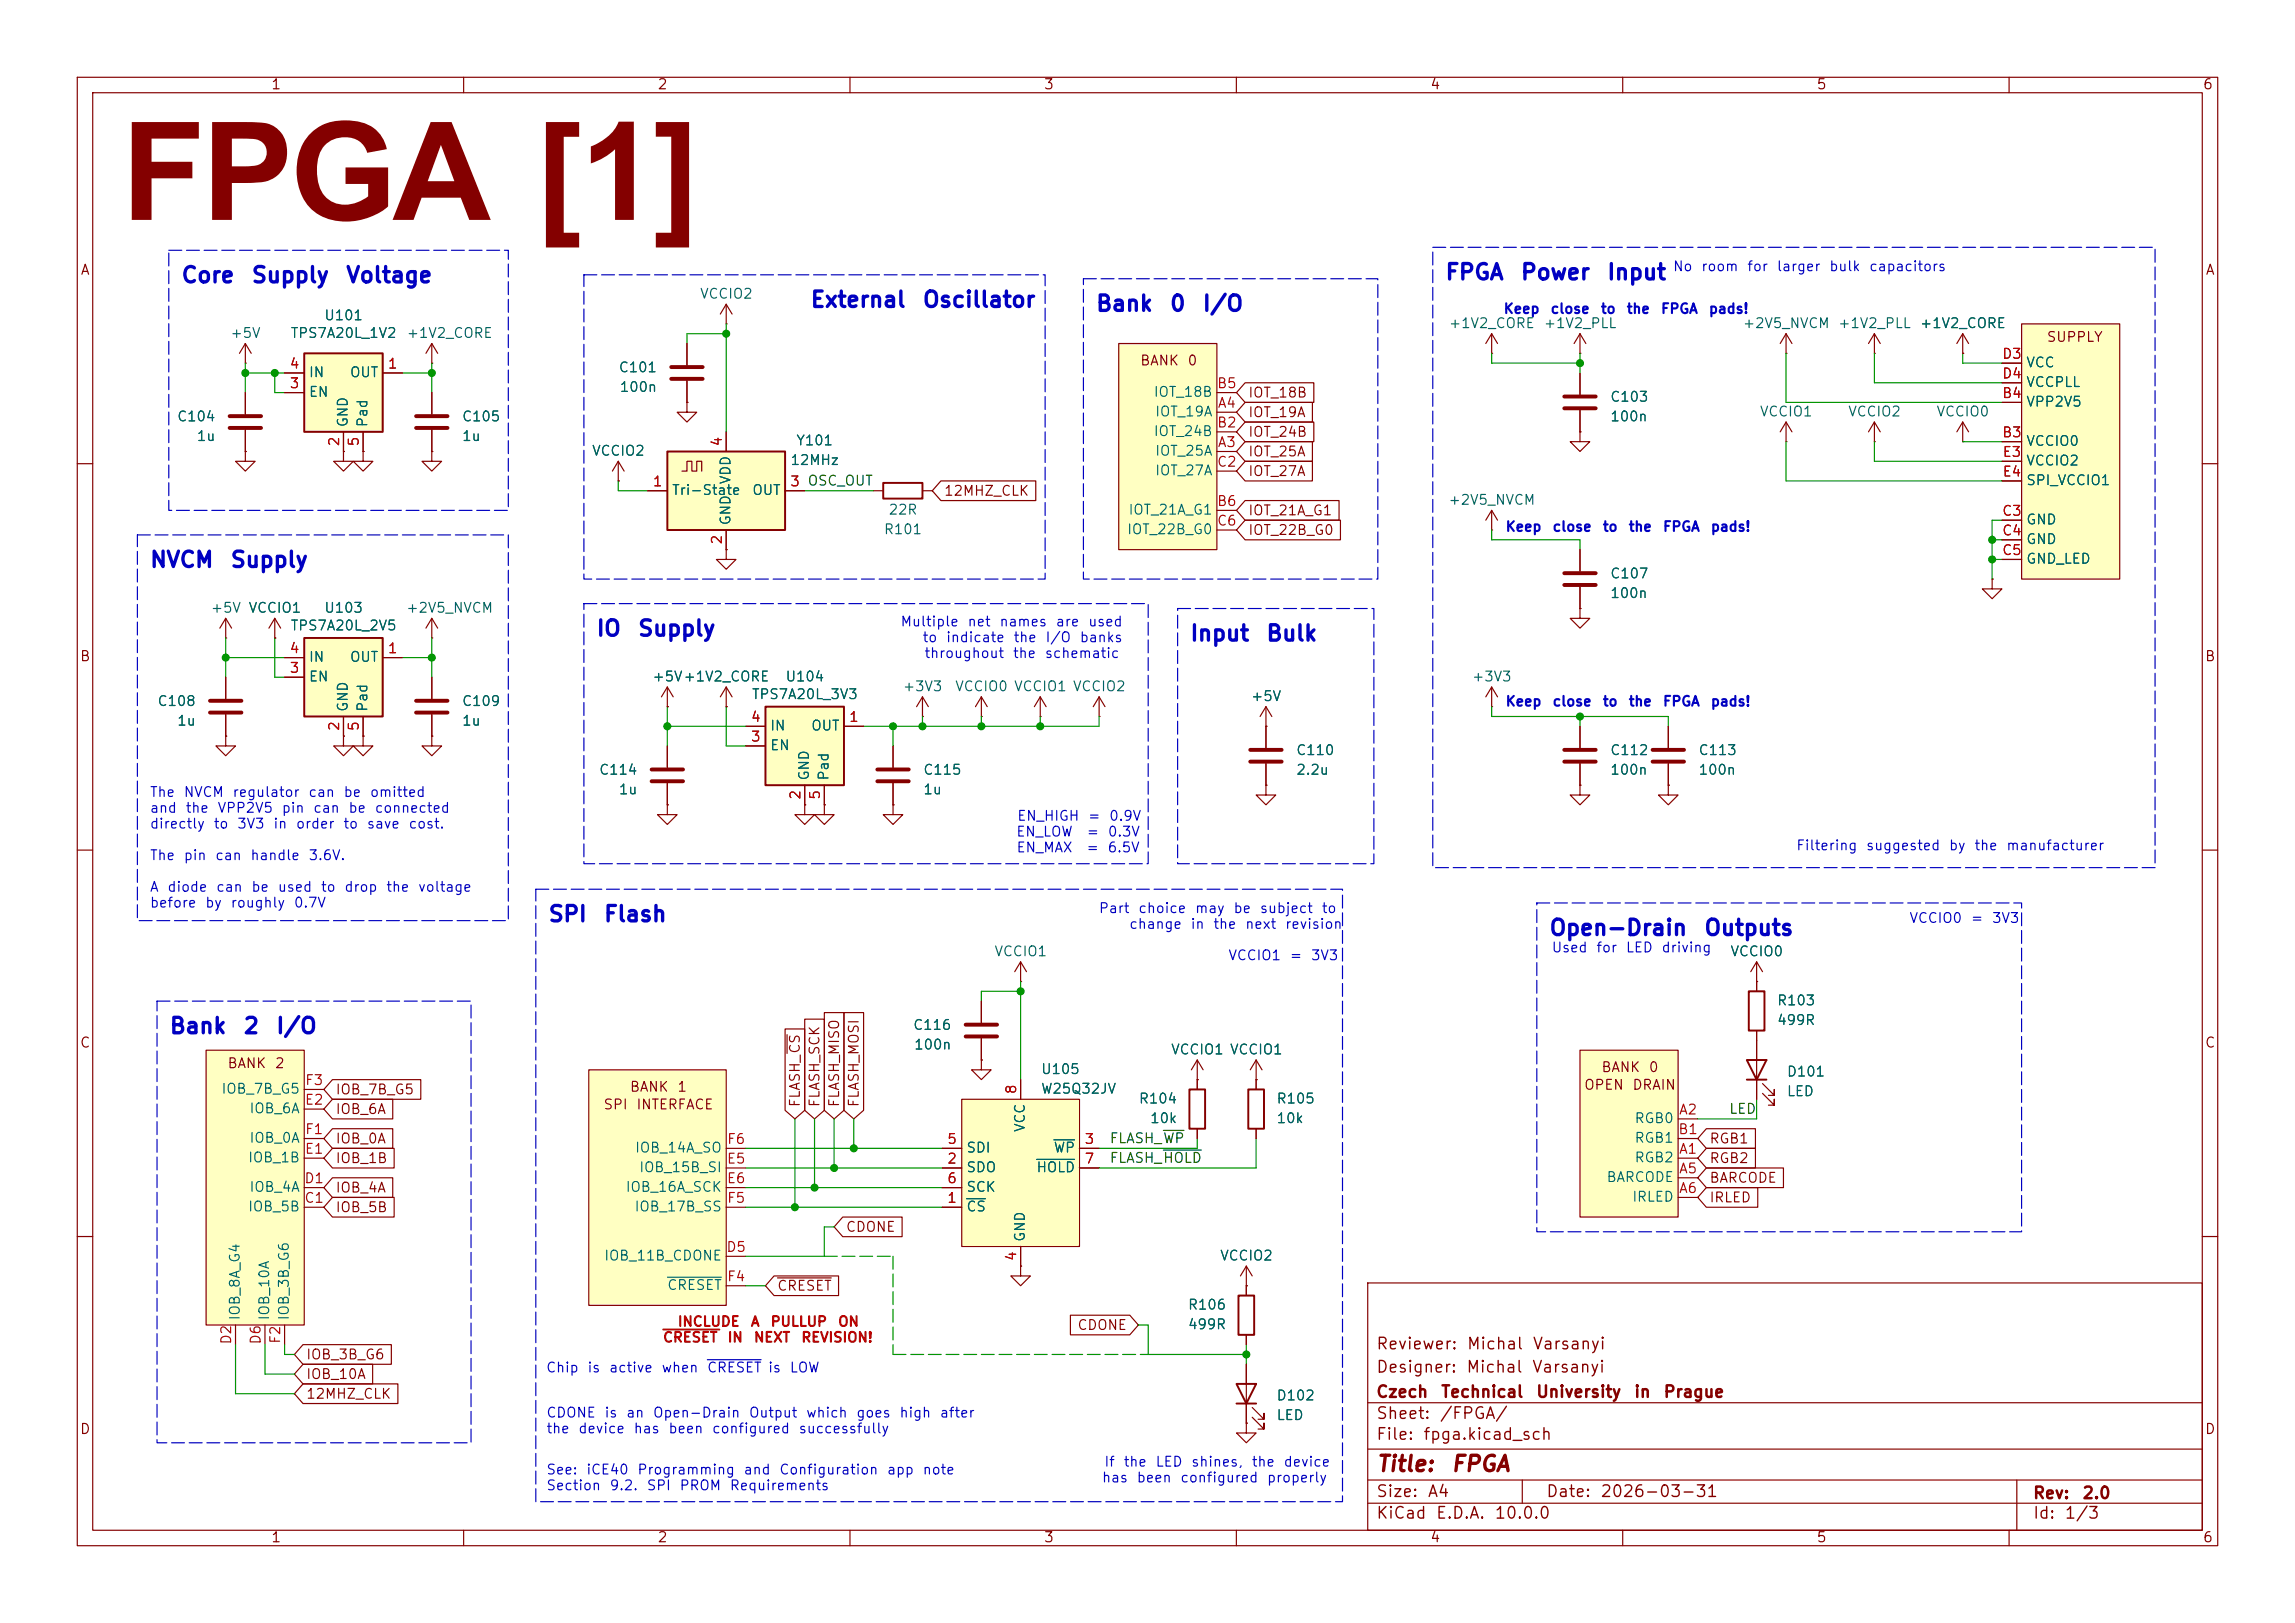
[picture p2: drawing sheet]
<svg xmlns="http://www.w3.org/2000/svg" width="297mm" height="210mm" viewBox="0 0 297 210" stroke-linecap="round" stroke-linejoin="round" font-family="sans-serif">
<defs><g id="words">
<text font-size="17.7" fill="#840000" x="15.7" y="28.5">FPGA [1]</text>
<g font-size="2" fill="#0000c2">
<text x="23.3" y="37.1">Core</text>
<text x="32.4" y="37.1">Supply</text>
<text x="44.7" y="37.1">Voltage</text>
<text x="104.8" y="40.3">External</text>
<text x="119.3" y="40.3">Oscillator</text>
<text x="141.7" y="40.8">Bank</text>
<text x="151.3" y="40.8">0</text>
<text x="155.5" y="40.8">I/O</text>
<text x="186.9" y="36.7">FPGA</text>
<text x="196.7" y="36.7">Power</text>
<text x="207.9" y="36.7">Input</text>
<text x="19.3" y="73.9">NVCM</text>
<text x="29.7" y="73.9">Supply</text>
<text x="77.1" y="82.8">IO</text>
<text x="82.4" y="82.8">Supply</text>
<text x="153.9" y="83.4">Input</text>
<text x="163.7" y="83.4">Bulk</text>
<text x="70.8" y="119.8">SPI</text>
<text x="78" y="119.8">Flash</text>
<text x="200.4" y="121.5">Open-Drain</text>
<text x="220.4" y="121.5">Outputs</text>
<text x="21.8" y="134.2">Bank</text>
<text x="31.4" y="134.2">2</text>
<text x="35.6" y="134.2">I/O</text>
</g>
<g font-size="2" fill="#840000">
<text x="178" y="190.9">Title:</text>
<text x="187.7" y="190.9">FPGA</text>
</g>
<g font-size="1.5" fill="#840000">
<text x="178" y="178">Designer:</text>
<text x="178" y="175">Reviewer:</text>
<text x="189.7" y="178">Michal</text>
<text x="189.7" y="175">Michal</text>
<text x="198.2" y="178">Varsanyi</text>
<text x="198.2" y="175">Varsanyi</text>
<text x="178" y="184">Sheet:</text>
<text x="178" y="181.2">Czech</text>
<text x="186.2" y="184">/FPGA/</text>
<text x="186.4" y="181.2">Technical</text>
<text x="198.7" y="181.2">University</text>
<text x="211.4" y="181.2">in</text>
<text x="215.2" y="181.2">Prague</text>
<text x="178" y="186.7">File:</text>
<text x="184.1" y="186.7">fpga.kicad_sch</text>
<text x="178" y="196.9">KiCad</text>
<text x="178" y="194.1">Size:</text>
<text x="184.7" y="194.1">A4</text>
<text x="185.7" y="196.9">E.D.A.</text>
<text x="193.3" y="196.9">10.0.0</text>
<text x="200" y="194.1">Date:</text>
<text x="207" y="194.1">2026-03-31</text>
<text x="263" y="194.3">Rev:</text>
<text x="263" y="196.9">Id:</text>
<text x="267.1" y="196.9">1/3</text>
<text x="269.4" y="194.3">2.0</text>
</g>
<g font-size="1.3" fill="#840000">
<text x="35" y="11.9">1</text>
<text x="85" y="11.9">2</text>
<text x="135" y="11.9">3</text>
<text x="185" y="11.9">4</text>
<text x="235" y="11.9">5</text>
<text x="285" y="11.9">6</text>
<text x="10.3" y="35.9">A</text>
<text x="285.3" y="35.9">A</text>
<text x="147.5" y="47.6">BANK</text>
<text x="153.6" y="47.6">0</text>
<text x="264.8" y="44.6">SUPPLY</text>
<text x="161.4" y="51.8">IOT_18B</text>
<text x="161.4" y="54.3">IOT_19A</text>
<text x="161.4" y="56.8">IOT_24B</text>
<text x="161.4" y="59.4">IOT_25A</text>
<text x="122.1" y="64.5">12MHZ_CLK</text>
<text x="161.4" y="61.9">IOT_27A</text>
<text x="161.4" y="67">IOT_21A_G1</text>
<text x="161.4" y="69.5">IOT_22B_G0</text>
<text x="10.3" y="85.9">B</text>
<text x="285.3" y="85.9">B</text>
<text x="10.3" y="135.9">C</text>
<text x="285.3" y="135.9">C</text>
<text x="29.4" y="138.5">BANK</text>
<text x="35.5" y="138.5">2</text>
<text x="43.3" y="141.9">IOB_7B_G5</text>
<text x="78" y="143.9">SPI</text>
<text x="81.4" y="141.6">BANK</text>
<text x="82.3" y="143.9">INTERFACE</text>
<text x="87.6" y="141.6">1</text>
<text x="103.8" y="143.4" transform="rotate(-90 103.8 143.4)">FLASH_CS</text>
<text x="106.4" y="143.4" transform="rotate(-90 106.4 143.4)">FLASH_SCK</text>
<text x="108.9" y="143.4" transform="rotate(-90 108.9 143.4)">FLASH_MISO</text>
<text x="111.4" y="143.4" transform="rotate(-90 111.4 143.4)">FLASH_MOSI</text>
<text x="204.9" y="141.3">OPEN</text>
<text x="207.2" y="139">BANK</text>
<text x="211.2" y="141.3">DRAIN</text>
<text x="213.3" y="139">0</text>
<text x="43.3" y="144.5">IOB_6A</text>
<text x="43.3" y="148.3">IOB_0A</text>
<text x="221.1" y="148.3">RGB1</text>
<text x="43.3" y="154.6">IOB_4A</text>
<text x="43.3" y="150.8">IOB_1B</text>
<text x="221.1" y="150.8">RGB2</text>
<text x="221.1" y="153.4">BARCODE</text>
<text x="221.1" y="155.9">IRLED</text>
<text x="43.3" y="157.2">IOB_5B</text>
<text x="109.4" y="159.7">CDONE</text>
<text x="100.5" y="167.3">CRESET</text>
<text x="139.3" y="172.4">CDONE</text>
<text x="39.5" y="178.8">IOB_10A</text>
<text x="39.5" y="176.2">IOB_3B_G6</text>
<text x="10.3" y="185.9">D</text>
<text x="39.5" y="181.3">12MHZ_CLK</text>
<text x="285.3" y="185.9">D</text>
<text x="35" y="199.9">1</text>
<text x="85" y="199.9">2</text>
<text x="135" y="199.9">3</text>
<text x="185" y="199.9">4</text>
<text x="235" y="199.9">5</text>
<text x="285" y="199.9">6</text>
</g>
<g font-size="1.3" fill="#0000c2">
<text x="216.4" y="35.4">No</text>
<text x="220.1" y="35.4">room</text>
<text x="226" y="35.4">for</text>
<text x="229.8" y="35.4">larger</text>
<text x="236.6" y="35.4">bulk</text>
<text x="241.8" y="35.4">capacitors</text>
<text x="194.5" y="40.9">Keep</text>
<text x="200.6" y="40.9">close</text>
<text x="207.1" y="40.9">to</text>
<text x="210.4" y="40.9">the</text>
<text x="214.9" y="40.9">FPGA</text>
<text x="221" y="40.9">pads!</text>
<text x="194.8" y="69.1">Keep</text>
<text x="200.8" y="69.1">close</text>
<text x="207.3" y="69.1">to</text>
<text x="210.7" y="69.1">the</text>
<text x="215.1" y="69.1">FPGA</text>
<text x="221.3" y="69.1">pads!</text>
<text x="116.4" y="81.4">Multiple</text>
<text x="119.3" y="83.4">to</text>
<text x="122.3" y="83.4">indicate</text>
<text x="125.1" y="81.4">net</text>
<text x="129.2" y="81.4">names</text>
<text x="131.1" y="83.4">the</text>
<text x="135.2" y="83.4">I/O</text>
<text x="136.5" y="81.4">are</text>
<text x="139.6" y="83.4">banks</text>
<text x="140.7" y="81.4">used</text>
<text x="119.5" y="85.5">throughout</text>
<text x="131" y="85.5">the</text>
<text x="135.1" y="85.5">schematic</text>
<text x="194.8" y="91.7">Keep</text>
<text x="200.8" y="91.7">close</text>
<text x="207.3" y="91.7">to</text>
<text x="210.7" y="91.7">the</text>
<text x="215.1" y="91.7">FPGA</text>
<text x="221.3" y="91.7">pads!</text>
<text x="19.3" y="103.4">The</text>
<text x="19.3" y="105.5">and</text>
<text x="19.3" y="107.5">directly</text>
<text x="23.7" y="103.4">NVCM</text>
<text x="23.9" y="105.5">the</text>
<text x="27.6" y="107.5">to</text>
<text x="28.1" y="105.5">VPP2V5</text>
<text x="30" y="103.4">regulator</text>
<text x="30.6" y="107.5">3V3</text>
<text x="35.3" y="107.5">in</text>
<text x="36.4" y="105.5">pin</text>
<text x="38.2" y="107.5">order</text>
<text x="39.8" y="103.4">can</text>
<text x="40.4" y="105.5">can</text>
<text x="44.3" y="107.5">to</text>
<text x="44.4" y="103.4">be</text>
<text x="45" y="105.5">be</text>
<text x="47.4" y="107.5">save</text>
<text x="47.8" y="103.4">omitted</text>
<text x="48.4" y="105.5">connected</text>
<text x="52.8" y="107.5">cost.</text>
<text x="131.5" y="106.5">EN_HIGH</text>
<text x="140.7" y="106.5">=</text>
<text x="143.4" y="106.5">0.9V</text>
<text x="19.3" y="111.6">The</text>
<text x="23.7" y="111.6">pin</text>
<text x="27.8" y="111.6">can</text>
<text x="32.3" y="111.6">handle</text>
<text x="39.8" y="111.6">3.6V.</text>
<text x="131.4" y="108.6">EN_LOW</text>
<text x="131.5" y="110.6">EN_MAX</text>
<text x="140.5" y="110.6">=</text>
<text x="140.5" y="108.6">=</text>
<text x="143.2" y="110.6">6.5V</text>
<text x="143.3" y="108.6">0.3V</text>
<text x="232.4" y="110.3">Filtering</text>
<text x="241.4" y="110.3">suggested</text>
<text x="252.1" y="110.3">by</text>
<text x="255.4" y="110.3">the</text>
<text x="259.5" y="110.3">manufacturer</text>
<text x="19.3" y="115.7">A</text>
<text x="19.3" y="117.8">before</text>
<text x="21.6" y="115.7">diode</text>
<text x="26.5" y="117.8">by</text>
<text x="27.9" y="115.7">can</text>
<text x="29.7" y="117.8">roughly</text>
<text x="32.4" y="115.7">be</text>
<text x="35.8" y="115.7">used</text>
<text x="37.9" y="117.8">0.7V</text>
<text x="41.4" y="115.7">to</text>
<text x="44.5" y="115.7">drop</text>
<text x="49.9" y="115.7">the</text>
<text x="54" y="115.7">voltage</text>
<text x="142.1" y="118.5">Part</text>
<text x="147.2" y="118.5">choice</text>
<text x="154.6" y="118.5">may</text>
<text x="159.5" y="118.5">be</text>
<text x="162.9" y="118.5">subject</text>
<text x="170.9" y="118.5">to</text>
<text x="247" y="119.7">VCCIO0</text>
<text x="254.9" y="119.7">=</text>
<text x="257.7" y="119.7">3V3</text>
<text x="146" y="120.5">change</text>
<text x="154" y="120.5">in</text>
<text x="156.9" y="120.5">the</text>
<text x="158.9" y="124.6">VCCIO1</text>
<text x="161" y="120.5">next</text>
<text x="166.2" y="120.5">revision</text>
<text x="166.8" y="124.6">=</text>
<text x="169.6" y="124.6">3V3</text>
<text x="200.7" y="123.5">Used</text>
<text x="206.5" y="123.5">for</text>
<text x="210.3" y="123.5">LED</text>
<text x="214.9" y="123.5">driving</text>
<text x="70.6" y="177.9">Chip</text>
<text x="75.9" y="177.9">is</text>
<text x="78.7" y="177.9">active</text>
<text x="85.5" y="177.9">when</text>
<text x="91.4" y="177.9">CRESET is</text>
<text x="102.1" y="177.9">LOW</text>
<text x="70.6" y="183.7">CDONE</text>
<text x="70.6" y="185.8">the</text>
<text x="74.7" y="185.8">device</text>
<text x="78.1" y="183.7">is</text>
<text x="80.9" y="183.7">an</text>
<text x="81.9" y="185.8">has</text>
<text x="84.4" y="183.7">Open-Drain</text>
<text x="86.4" y="185.8">been</text>
<text x="92" y="185.8">configured</text>
<text x="96.8" y="183.7">Output</text>
<text x="103.3" y="185.8">successfully</text>
<text x="104.2" y="183.7">which</text>
<text x="110.7" y="183.7">goes</text>
<text x="116.3" y="183.7">high</text>
<text x="121.5" y="183.7">after</text>
<text x="70.6" y="191.1">See:</text>
<text x="75.8" y="191.1">iCE40</text>
<text x="82.4" y="191.1">Programming</text>
<text x="96.1" y="191.1">and</text>
<text x="100.8" y="191.1">Configuration</text>
<text x="114.7" y="191.1">app</text>
<text x="119.3" y="191.1">note</text>
<text x="142.8" y="190.1">If</text>
<text x="145.3" y="190.1">the</text>
<text x="149.4" y="190.1">LED</text>
<text x="154.1" y="190.1">shines,</text>
<text x="161.9" y="190.1">the</text>
<text x="166" y="190.1">device</text>
<text x="70.6" y="193.2">Section</text>
<text x="78.8" y="193.2">9.2.</text>
<text x="83.6" y="193.2">SPI</text>
<text x="87.9" y="193.2">PROM</text>
<text x="94.3" y="193.2">Requirements</text>
<text x="142.5" y="192.1">has</text>
<text x="147" y="192.1">been</text>
<text x="152.7" y="192.1">configured</text>
<text x="163.9" y="192.1">properly</text>
</g>
<g font-size="1.3" fill="#006464">
<text x="41.9" y="41.8">U101</text>
<text x="90.5" y="39">VCCIO2</text>
<text x="29.7" y="44">+5V</text>
<text x="37.5" y="44">TPS7A20L_1V2</text>
<text x="52.5" y="44">+1V2_CORE</text>
<text x="187.4" y="42.8">+1V2_CORE</text>
<text x="199.7" y="42.8">+1V2_PLL</text>
<text x="225.4" y="42.8">+2V5_NVCM</text>
<text x="237.8" y="42.8">+1V2_PLL</text>
<text x="248.4" y="42.8">+1V2_CORE</text>
<text x="262.1" y="47.9">VCC</text>
<text x="39.9" y="51.7">EN</text>
<text x="39.9" y="49.1">IN</text>
<text x="45.2" y="49.1">OUT</text>
<text x="80" y="48.5">C101</text>
<text x="80.1" y="51">100n</text>
<text x="149.2" y="51.7">IOT_18B</text>
<text x="208.3" y="52.3">C103</text>
<text x="262.1" y="52.9">VPP2V5</text>
<text x="262.1" y="50.4">VCCPLL</text>
<text x="22.8" y="54.8">C104</text>
<text x="25.4" y="57.4">1u</text>
<text x="45.3" y="55.4" transform="rotate(-90 45.3 55.4)">GND</text>
<text x="47.9" y="55.4" transform="rotate(-90 47.9 55.4)">Pad</text>
<text x="59.7" y="54.8">C105</text>
<text x="59.7" y="57.4">1u</text>
<text x="76.5" y="59.3">VCCIO2</text>
<text x="102.9" y="57.9">Y101</text>
<text x="149.2" y="56.7">IOT_24B</text>
<text x="149.4" y="59.3">IOT_25A</text>
<text x="149.4" y="54.2">IOT_19A</text>
<text x="208.3" y="54.8">100n</text>
<text x="227.7" y="54.2">VCCIO1</text>
<text x="239.1" y="54.2">VCCIO2</text>
<text x="250.5" y="54.2">VCCIO0</text>
<text x="262.1" y="58">VCCIO0</text>
<text x="86.9" y="64.4">Tri-State</text>
<text x="94.8" y="62.8" transform="rotate(-90 94.8 62.8)">VDD</text>
<text x="97.3" y="64.4">OUT</text>
<text x="102.2" y="60.5">12MHz</text>
<text x="149.4" y="61.8">IOT_27A</text>
<text x="187.3" y="65.6">+2V5_NVCM</text>
<text x="262.1" y="60.6">VCCIO2</text>
<text x="262.1" y="63.1">SPI_VCCIO1</text>
<text x="94.8" y="68.1" transform="rotate(-90 94.8 68.1)">GND</text>
<text x="114.3" y="69.4">R101</text>
<text x="114.9" y="66.9">22R</text>
<text x="145.8" y="69.4">IOT_22B_G0</text>
<text x="145.9" y="66.9">IOT_21A_G1</text>
<text x="262.1" y="68.2">GND</text>
<text x="262.1" y="70.7">GND</text>
<text x="208.3" y="75.2">C107</text>
<text x="208.3" y="77.7">100n</text>
<text x="262.1" y="73.3">GND_LED</text>
<text x="27.2" y="79.6">+5V</text>
<text x="32.1" y="79.6">VCCIO1</text>
<text x="37.5" y="81.9">TPS7A20L_2V5</text>
<text x="41.9" y="79.6">U103</text>
<text x="52.5" y="79.6">+2V5_NVCM</text>
<text x="39.9" y="88.5">EN</text>
<text x="39.9" y="86">IN</text>
<text x="45.2" y="86">OUT</text>
<text x="84.3" y="88.5">+5V+1V2_CORE</text>
<text x="101.6" y="88.5">U104</text>
<text x="116.7" y="89.8">+3V3</text>
<text x="123.5" y="89.8">VCCIO0 VCCIO1 VCCIO2</text>
<text x="190.4" y="88.5">+3V3</text>
<text x="20.3" y="91.7">C108</text>
<text x="22.8" y="94.2">1u</text>
<text x="45.3" y="92.2" transform="rotate(-90 45.3 92.2)">GND</text>
<text x="47.9" y="92.2" transform="rotate(-90 47.9 92.2)">Pad</text>
<text x="59.7" y="91.7">C109</text>
<text x="59.7" y="94.2">1u</text>
<text x="97.2" y="90.8">TPS7A20L_3V3</text>
<text x="99.6" y="94.8">IN</text>
<text x="104.9" y="94.8">OUT</text>
<text x="161.8" y="91">+5V</text>
<text x="77.4" y="100.6">C114</text>
<text x="99.6" y="97.4">EN</text>
<text x="105" y="101.1" transform="rotate(-90 105 101.1)">GND</text>
<text x="107.5" y="101.1" transform="rotate(-90 107.5 101.1)">Pad</text>
<text x="119.4" y="100.6">C115</text>
<text x="167.6" y="98">C110</text>
<text x="167.6" y="100.6">2.2u</text>
<text x="208.3" y="98">C112</text>
<text x="208.3" y="100.6">100n</text>
<text x="219.7" y="98">C113</text>
<text x="219.7" y="100.6">100n</text>
<text x="80" y="103.1">1u</text>
<text x="119.4" y="103.1">1u</text>
<text x="128.6" y="124.1">VCCIO1</text>
<text x="223.8" y="124.1">VCCIO0</text>
<text x="229.9" y="130.4">R103</text>
<text x="118.1" y="133.6">C116</text>
<text x="118.2" y="136.1">100n</text>
<text x="151.5" y="136.8">VCCIO1 VCCIO1</text>
<text x="229.9" y="132.9">499R</text>
<text x="28.6" y="141.8">IOB_7B_G5</text>
<text x="134.6" y="141.8">W25Q32JV</text>
<text x="134.6" y="139.3">U105</text>
<text x="147.3" y="143.1">R104</text>
<text x="165.1" y="143.1">R105</text>
<text x="231.1" y="139.6">D101</text>
<text x="231.1" y="142.2">LED</text>
<text x="32.2" y="144.4">IOB_6A</text>
<text x="32.2" y="148.2">IOB_0A</text>
<text x="82.1" y="149.5">IOB_14A_SO</text>
<text x="125" y="149.5">SDI</text>
<text x="132.9" y="146.6" transform="rotate(-90 132.9 146.6)">VCC</text>
<text x="136.3" y="149.5">WP</text>
<text x="148.7" y="145.6">10k</text>
<text x="165.1" y="145.6">10k</text>
<text x="211.4" y="145.6">RGB0</text>
<text x="211.4" y="148.2">RGB1</text>
<text x="32" y="150.7">IOB_1B</text>
<text x="32.2" y="154.5">IOB_4A</text>
<text x="80.9" y="154.5">IOB_16A_SCK</text>
<text x="82.6" y="152">IOB_15B_SI</text>
<text x="125" y="152">SDO</text>
<text x="125" y="154.5">SCK</text>
<text x="134" y="152">HOLD</text>
<text x="207.8" y="153.3">BARCODE</text>
<text x="211.1" y="155.8">IRLED</text>
<text x="211.4" y="150.7">RGB2</text>
<text x="32" y="157.1">IOB_5B</text>
<text x="82" y="157.1">IOB_17B_SS</text>
<text x="125" y="157.1">CS</text>
<text x="132.9" y="160.8" transform="rotate(-90 132.9 160.8)">GND</text>
<text x="78.1" y="163.4">IOB_11B_CDONE</text>
<text x="86.3" y="167.2">CRESET</text>
<text x="157.8" y="163.4">VCCIO2</text>
<text x="31.3" y="170.9" transform="rotate(-90 31.3 170.9)">IOB_8A_G4</text>
<text x="35.2" y="170.9" transform="rotate(-90 35.2 170.9)">IOB_10A</text>
<text x="37.7" y="170.9" transform="rotate(-90 37.7 170.9)">IOB_3B_G6</text>
<text x="153.6" y="169.8">R106</text>
<text x="153.6" y="172.3">499R</text>
<text x="165.1" y="181.5">D102</text>
<text x="165.1" y="184.1">LED</text>
</g>
<g font-size="1.3" fill="#a90000">
<text x="259" y="46.7">D3</text>
<text x="37.4" y="50.5">3</text>
<text x="37.4" y="48">4</text>
<text x="50.1" y="48">1</text>
<text x="157.4" y="50.5">B5</text>
<text x="157.5" y="53.1">A4</text>
<text x="259" y="51.8">B4</text>
<text x="259" y="49.3">D4</text>
<text x="44.2" y="57.9" transform="rotate(-90 44.2 57.9)">2</text>
<text x="46.7" y="57.9" transform="rotate(-90 46.7 57.9)">5</text>
<text x="93.7" y="57.9" transform="rotate(-90 93.7 57.9)">4</text>
<text x="157.4" y="55.6">B2</text>
<text x="157.5" y="58.2">A3</text>
<text x="259" y="56.9">B3</text>
<text x="259.1" y="59.4">E3</text>
<text x="84.4" y="63.2">1</text>
<text x="102.2" y="63.2">3</text>
<text x="157.4" y="65.8">B6</text>
<text x="157.4" y="60.7">C2</text>
<text x="259.1" y="62">E4</text>
<text x="93.7" y="70.6" transform="rotate(-90 93.7 70.6)">2</text>
<text x="157.4" y="68.3">C6</text>
<text x="259" y="67.1">C3</text>
<text x="259" y="69.6">C4</text>
<text x="259" y="72.1">C5</text>
<text x="37.4" y="87.4">3</text>
<text x="37.4" y="84.8">4</text>
<text x="50.1" y="84.8">1</text>
<text x="44.2" y="94.7" transform="rotate(-90 44.2 94.7)">2</text>
<text x="46.7" y="94.7" transform="rotate(-90 46.7 94.7)">5</text>
<text x="97.1" y="93.7">4</text>
<text x="109.8" y="93.7">1</text>
<text x="97.1" y="96.3">3</text>
<text x="103.9" y="103.6" transform="rotate(-90 103.9 103.6)">2</text>
<text x="106.4" y="103.6" transform="rotate(-90 106.4 103.6)">5</text>
<text x="39.4" y="143.3">E2</text>
<text x="39.4" y="140.7">F3</text>
<text x="131.8" y="141.7" transform="rotate(-90 131.8 141.7)">8</text>
<text x="39.4" y="149.6">E1</text>
<text x="39.4" y="147.1">F1</text>
<text x="94" y="148.3">F6</text>
<text x="122.5" y="148.3">5</text>
<text x="140.3" y="148.3">3</text>
<text x="217.1" y="147.1">B1</text>
<text x="217.2" y="149.6">A1</text>
<text x="217.2" y="144.5">A2</text>
<text x="39.3" y="156">C1</text>
<text x="39.3" y="153.4">D1</text>
<text x="94" y="150.9">E5</text>
<text x="94" y="153.4">E6</text>
<text x="94" y="156">F5</text>
<text x="122.5" y="156">1</text>
<text x="122.5" y="150.9">2</text>
<text x="122.5" y="153.4">6</text>
<text x="140.3" y="150.9">7</text>
<text x="217.2" y="152.1">A5</text>
<text x="217.2" y="154.7">A6</text>
<text x="93.9" y="162.3">D5</text>
<text x="94" y="166.1">F4</text>
<text x="131.8" y="163.3" transform="rotate(-90 131.8 163.3)">4</text>
<text x="36.6" y="174" transform="rotate(-90 36.6 174)">F2</text>
<text x="30.2" y="174.1" transform="rotate(-90 30.2 174.1)">D2</text>
<text x="34" y="174.1" transform="rotate(-90 34 174.1)">D6</text>
</g>
<g font-size="1.3" fill="#0f0f0f">
<text x="104.4" y="63.2">OSC_OUT</text>
<text x="143.5" y="148.2">FLASH_WP</text>
<text x="223.7" y="144.4">LED</text>
<text x="143.5" y="150.8">FLASH_HOLD</text>
</g>
<g font-size="1.3" fill="#f00">
<text x="87.6" y="172">INCLUDE</text>
<text x="97.1" y="172">A</text>
<text x="99.6" y="172">PULLUP</text>
<text x="108.4" y="172">ON</text>
<text x="85.7" y="174">CRESET</text>
<text x="94.1" y="174">IN</text>
<text x="97.5" y="174">NEXT</text>
<text x="103.6" y="174">REVISION!</text>
</g>
</g></defs>
<g fill="none" stroke="#840000" stroke-width=".15">
<path d="M10 10h277v190h-277zM12 12h273v186h-273zM60 10v2M110 10v2M160 10v2M210 10v2M260 10v2M44.4 58.4v1.3h1.3l-1.3 1.3-1.2-1.3h1.2M44.4 58.4h.1M10 60h2M285 60h2M10 110h2"/>
<path d="M285 110h2M154.9 139.7v1.3M154.9 146.1v1.2M10 160h2M177 166h108v32h-108zM285 160h2M60 198v2M110 198v2M160 198v2M177 194.5h108M177 191.5h108M177 187.5h108"/>
<path d="M177 181.5h108M197 191.5v3M210 198v2M260 198v2M261 191.5v6.5"/>
</g>
<path d="M153.9 141h2.1v5.1h-2.1z" fill="none" stroke="#840000" stroke-width=".25"/>
<path d="M86.4 58.4h15.2v10.2h-15.2z" fill="#ffffc2"/>
<path d="M86.4 58.4h15.2v10.2h-15.2z" fill="none" stroke="#840000" stroke-width=".25"/>
<g fill="none" stroke="#840000" stroke-width=".15">
<path d="M80 59.7l.8 1.3M80 59.7l-.8 1.3M80 59.7v2.5M94 55.9v2.5M80 62.2h.1M83.8 63.5h2.6M88.3 61h.6v-1.3h.6v1.3h.7v-1.3h.6v1.3M94 68.6v2.5M101.6 63.5h2.5M29.2 82.6h.1M29.2 95.3v1.2h-1.3l1.3 1.3 1.3-1.3h-1.3M29.2 95.3h.1"/>
<path d="M29.2 80l-.8 1.3M29.2 80l.8 1.3M29.2 80v2.6M29.2 87.6v2.8M29.2 92.5v2.8M35.6 82.6h.1M35.6 80l.7 1.3M35.6 80l-.8 1.3M35.6 80v2.6"/>
</g>
<path d="M27.2 90.7h4M27.2 92.2h4" fill="none" stroke="#840000" stroke-width=".51"/>
<path d="M99.1 91.4h10.1v10.2h-10.1z" fill="#ffffc2"/>
<path d="M114.3 62.5h5.1v2h-5.1zM99.1 91.4h10.1v10.2h-10.1z" fill="none" stroke="#840000" stroke-width=".25"/>
<g fill="none" stroke="#840000" stroke-width=".15">
<path d="M94 39.4l.7 1.2M94 39.4l-.8 1.2M94 39.4v2.5M88.9 52.1v1.2h1.3l-1.3 1.3-1.3-1.3h1.3M88.9 52.1h.1M94 41.9h.1M231.1 45.7h.1M231.1 43.2l.8 1.3M231.1 43.2l-.7 1.3M231.1 43.2v2.5M94 71.1v1.3h1.2l-1.2 1.3-1.3-1.3h1.3M94 71.1h.1"/>
<path d="M113 63.5h1.3M119.4 63.5h1.2M44.4 95.3v1.2h1.3l-1.3 1.3-1.2-1.3h1.2M44.4 95.3h.1M47 95.3v1.2h1.3l-1.3 1.3-1.3-1.3h1.3M47 95.3h.1M55.9 95.3v1.2h1.2l-1.2 1.3-1.3-1.3h1.3M55.9 95.3h.1M55.9 87.6v2.8M55.9 92.5v2.8M86.4 91.4h.1M86.4 88.9v2.5"/>
<path d="M86.4 96.5v2.8M86.4 88.9l-.8 1.3M86.4 88.9l.7 1.3M96.5 94h2.6M96.5 96.5h2.6M109.2 94h2.6M115.6 96.5v2.8M119.4 92.7h.1M119.4 90.2l.7 1.2M119.4 90.2l-.8 1.2M119.4 90.2v2.5M127 92.7h.1"/>
<path d="M127 90.2l.8 1.2M127 90.2l-.8 1.2M127 90.2v2.5M134.6 92.7h.1M134.6 90.2l.8 1.2M134.6 90.2l-.7 1.2M134.6 90.2v2.5M142.2 92.7h.1M142.2 90.2l.8 1.2M142.2 90.2l-.7 1.2M142.2 90.2v2.5M86.4 104.1v1.3h-1.3l1.3 1.3 1.2-1.3h-1.2"/>
<path d="M86.4 104.1h.1M86.4 101.3v2.8M104.1 101.6v2.5M106.7 101.6v2.5M115.6 104.1v1.3h1.2l-1.2 1.3-1.3-1.3h1.3M115.6 104.1h.1M115.6 101.3v2.8"/>
</g>
<path d="M53.8 90.7h4.1M53.8 92.2h4.1M84.3 99.6h4.1M113.5 99.6h4.1M84.3 101.1h4.1M113.5 101.1h4.1" fill="none" stroke="#840000" stroke-width=".51"/>
<path d="M39.4 82.6h10.1v10.1h-10.1z" fill="#ffffc2"/>
<path d="M39.4 82.6h10.1v10.1h-10.1z" fill="none" stroke="#840000" stroke-width=".25"/>
<path d="M36.8 85.1h2.6M36.8 87.6h2.6M44.4 92.7v2.6M47 92.7v2.6M49.5 85.1h2.6M55.9 82.6h.1M55.9 80l.7 1.3M55.9 80l-.8 1.3M55.9 80v2.6" fill="none" stroke="#840000" stroke-width=".15"/>
<path d="M39.4 45.7h10.1v10.2h-10.1z" fill="#ffffc2"/>
<path d="M39.4 45.7h10.1v10.2h-10.1z" fill="none" stroke="#840000" stroke-width=".25"/>
<path d="M36.8 48.3h2.6M36.8 50.8h2.6M44.4 55.9v2.5M47 55.9v2.5M49.5 48.3h2.6" fill="none" stroke="#840000" stroke-width=".15"/>
<path d="M204.5 135.9h12.7v21.6h-12.7z" fill="#ffffc2"/>
<path d="M204.5 135.9h12.7v21.6h-12.7zM217.2 149.9h2.5M217.2 144.8h2.5M217.2 152.4h2.5M217.2 154.9h2.5M217.2 147.3h2.5" fill="none" stroke="#840000" stroke-width=".15"/>
<path d="M76.2 138.4h17.8v30.5h-17.8z" fill="#ffffc2"/>
<g fill="none" stroke="#840000" stroke-width=".15">
<path d="M76.2 138.4h17.8v30.5h-17.8zM227.3 127v1.3M227.3 133.4v8.8M94 151.1h2.5M94 153.7h2.5M94 156.2h2.5M94 148.6h2.5M228.1 141.5l1.5 1.5v-.8v.8h-.7M228.1 140.2l1.5 1.5v-.7v.7h-.7M94 162.6h2.5M94 166.4h2.5M161.3 166.4h.1"/>
<path d="M161.3 163.8v3.8M161.3 172.7v1.3M161.3 176.5v7.7M161.3 163.8l.8 1.3M161.3 163.8l-.8 1.3M161.3 184.2v1.2h1.3l-1.3 1.3-1.3-1.3h1.3M161.3 184.2h.1M162.1 183.4l1.5 1.5v-.7v.7h-.8M162.1 182.1l1.5 1.5v-.7v.7h-.8"/>
</g>
<path d="M86.4 165.3h6.9" fill="none" stroke="#006464" stroke-width=".15"/>
<path d="M226.1 137.2h2.5l-1.3 2.5zM226.1 139.7h2.5M226.3 128.3h2v5.1h-2zM160 179.1h2.6l-1.3 2.5zM160.3 167.6h2v5.1h-2zM160 181.6h2.6" fill="none" stroke="#840000" stroke-width=".25"/>
<path d="M124.5 142.2h15.2v19.1h-15.2z" fill="#ffffc2"/>
<path d="M132.1 139.7v2.5M121.9 156.2h2.6M121.9 151.1h2.6M121.9 148.6h2.6M121.9 153.7h2.6M124.5 142.2h15.2v19.1h-15.2zM139.7 151.1h2.5M139.7 148.6h2.5M132.1 161.3v2.5" fill="none" stroke="#840000" stroke-width=".15"/>
<path d="M125.1 155.1h2.4M134.2 150h4.9M136.4 147.5h2.7" fill="none" stroke="#006464" stroke-width=".15"/>
<path d="M26.7 135.9h12.7v35.6h-12.7z" fill="#ffffc2"/>
<g fill="none" stroke="#840000" stroke-width=".15">
<path d="M242.6 57.2h.1M242.6 54.6l-.8 1.3M242.6 54.6l.7 1.3M242.6 54.6v2.6M257.8 74.9v1.3h1.3l-1.3 1.3-1.3-1.3h1.3M257.8 74.9h.1M26.7 135.9h12.7v35.6h-12.7zM227.3 127h.1M227.3 124.5l.8 1.2M227.3 124.5l-.7 1.2M227.3 124.5v2.5M39.4 156.2h2.5"/>
<path d="M39.4 153.7h2.5M39.4 149.9h2.5M39.4 143.5h2.5M39.4 147.3h2.5M39.4 141h2.5M30.5 171.5v2.5M34.3 171.5v2.5M36.8 171.5v2.5"/>
</g>
<path d="M261.6 41.9h12.7v33h-12.7z" fill="#ffffc2"/>
<g fill="none" stroke="#840000" stroke-width=".15">
<path d="M31.7 58.4v1.3h-1.2l1.2 1.3 1.3-1.3h-1.3M31.7 58.4h.1M31.7 47h.1M31.7 44.5v2.5M31.7 50.8v2.8M31.7 55.6v2.8M31.7 44.5l-.7 1.2M31.7 44.5l.8 1.2M47 58.4v1.3h1.3l-1.3 1.3-1.3-1.3h1.3M47 58.4h.1M55.9 47h.1M55.9 58.4v1.3h1.2l-1.2 1.3-1.3-1.3h1.3"/>
<path d="M55.9 58.4h.1M55.9 44.5v2.5M55.9 50.8v2.8M55.9 55.6v2.8M55.9 44.5l.7 1.2M55.9 44.5l-.8 1.2M88.9 44.5v2.7M88.9 49.3v2.8M193 45.7h.1M193 43.2v2.5M193 43.2l-.7 1.3M193 43.2l.8 1.3"/>
<path d="M204.5 45.7h.1M204.5 43.2l.7 1.3M204.5 43.2l-.8 1.3M204.5 43.2v2.5M231.1 57.2h.1M231.1 54.6l-.7 1.3M231.1 54.6l.8 1.3M231.1 54.6v2.6M242.6 45.7h.1M242.6 43.2l.7 1.3M242.6 43.2l-.8 1.3M242.6 43.2v2.5"/>
<path d="M254 45.7h.1M254 57.2h.1M254 43.2l.8 1.3M254 43.2l-.8 1.3M254 43.2v2.5M254 54.6v2.6M254 54.6l-.8 1.3M254 54.6l.8 1.3M259.1 57.2h2.5M259.1 52.1h2.5M259.1 47h2.5M259.1 49.5h2.5"/>
<path d="M259.1 59.7h2.5M261.6 41.9h12.7v33h-12.7zM259.1 67.3h2.5M259.1 69.9h2.5M259.1 72.4h2.5M259.1 62.2h2.5M193 91.4h.1M193 88.9l.8 1.3M193 88.9l-.7 1.3M193 88.9v2.5M215.9 94v2.8M215.9 98.8v2.8"/>
<path d="M127 137.2v1.2h1.3l-1.3 1.3-1.3-1.3h1.3M127 137.2h.1M127 129.5v2.8M127 134.4v2.8M132.1 127h.1M132.1 124.5l.7 1.2M132.1 124.5l-.8 1.2M132.1 124.5v2.5M154.9 139.7h.1M154.9 137.2l.8 1.2M154.9 137.2l-.7 1.2M154.9 137.2v2.5"/>
<path d="M162.6 139.7h.1M162.6 137.2l.7 1.2M162.6 137.2l-.8 1.2M162.6 137.2v3.8M162.6 146.1v1.2M132.1 163.8v1.3h1.2l-1.2 1.3-1.3-1.3h1.3M132.1 163.8h.1"/>
</g>
<path d="M29.7 53.8h4.1M29.7 55.4h4.1M53.8 53.8h4.1M53.8 55.4h4.1M86.9 47.5h4M86.9 49h4M213.9 97h4M213.9 98.6h4M125 132.6h4M125 134.1h4" fill="none" stroke="#840000" stroke-width=".51"/>
<path d="M161.5 141h2.1v5.1h-2.1z" fill="none" stroke="#840000" stroke-width=".25"/>
<path d="M144.8 44.5h12.7v26.6h-12.7z" fill="#ffffc2"/>
<g fill="none" stroke="#840000" stroke-width=".15">
<path d="M31.7 58.4h.1M31.7 50.8v2.8M31.7 55.6v2.8M36.8 50.8h2.6M36.8 48.3h2.6M44.4 58.4h.1M44.4 55.9v2.5M47 58.4h.1M47 55.9v2.5M49.5 48.3h2.6M55.9 58.4h.1M55.9 50.8v2.8"/>
<path d="M55.9 55.6v2.8M88.9 52.1h.1M88.9 44.5v2.7M88.9 49.3v2.8M94 55.9v2.5M144.8 44.5h12.7v26.6h-12.7zM157.5 58.4h2.5M157.5 53.3h2.5M157.5 55.9h2.5M157.5 50.8h2.5M161.1 52.1h8.7v2.5h-8.7l-1.1-1.3zM161.1 54.6h8.9v2.6h-8.9l-1.1-1.3z"/>
<path d="M161.1 57.1h8.7v2.6h-8.7l-1.1-1.3zM161.1 49.5h8.9v2.6h-8.9l-1.1-1.3zM161.1 59.7h8.7v2.5h-8.7l-1.1-1.2zM204.5 55.9v1.3h1.2l-1.2 1.2-1.3-1.2h1.3M204.5 55.9h.1M204.5 48.3v2.8M204.5 53.1v2.8M254 45.7h.1M259.1 57.2h2.5M259.1 52.1h2.5M259.1 47h2.5M259.1 49.5h2.5"/>
<path d="M259.1 59.7h2.5M80 62.2h.1M83.8 63.5h2.6M94 71.1h.1M94 68.6v2.5M101.6 63.5h2.5M157.5 66h2.5M157.5 61h2.5M157.5 68.6h2.5M161.1 64.8h12.2v2.5h-12.2l-1.1-1.3zM161.1 67.3h12.4v2.6h-12.4l-1.1-1.3zM193 68.6h.1"/>
<path d="M193 66l.8 1.3M193 66l-.7 1.3M193 66v2.6M204.5 78.7v1.3h1.2l-1.2 1.3-1.3-1.3h1.3M204.5 78.7h.1M204.5 71.1v2.8M204.5 75.9v2.8M257.8 74.9h.1M259.1 67.3h2.5M259.1 69.9h2.5M259.1 72.4h2.5M259.1 62.2h2.5"/>
<path d="M29.2 95.3h.1M29.2 87.6v2.8M29.2 92.5v2.8M35.6 82.6h.1M36.8 85.1h2.6M36.8 87.6h2.6M44.4 95.3h.1M44.4 92.7v2.6M47 95.3h.1M47 92.7v2.6M49.5 85.1h2.6M55.9 95.3h.1"/>
<path d="M55.9 87.6v2.8M55.9 92.5v2.8M86.4 91.4h.1M86.4 96.5v2.8M94 91.4h.1M94 88.9l.7 1.3M94 88.9l-.8 1.3M94 88.9v2.5M96.5 94h2.6M96.5 96.5h2.6M109.2 94h2.6M115.6 96.5v2.8"/>
<path d="M163.8 94h.1M163.8 91.4l-.7 1.3M163.8 91.4l.8 1.3M163.8 91.4v5.4M163.8 98.8v2.8M204.5 94v2.8M204.5 98.8v2.8M215.9 94v2.8M215.9 98.8v2.8M86.4 104.1h.1M86.4 101.3v2.8M104.1 104.1v1.3h1.3l-1.3 1.3-1.2-1.3h1.2"/>
<path d="M104.1 104.1h.1M104.1 101.6v2.5M106.7 104.1v1.3h1.2l-1.2 1.3-1.3-1.3h1.3M106.7 104.1h.1M106.7 101.6v2.5M115.6 104.1h.1M115.6 101.3v2.8M163.8 101.6v1.3h1.3l-1.3 1.2-1.2-1.2h1.2M163.8 101.6h.1M204.5 101.6v1.3h1.2l-1.2 1.2-1.3-1.2h1.3M204.5 101.6h.1M215.9 101.6v1.3h1.3l-1.3 1.2-1.3-1.2h1.3"/>
<path d="M215.9 101.6h.1M43 139.7h11.5v2.5h-11.5l-1.1-1.2zM101.6 133.1h2.5v10.6l-1.2 1.1-1.3-1.1zM101.9 133.9v2.4M104.1 131.9h2.6v11.8l-1.3 1.1-1.3-1.1zM106.7 131h2.5v12.7l-1.3 1.1-1.2-1.1zM109.2 131h2.6v12.7l-1.3 1.1-1.3-1.1zM127 137.2h.1M127 129.5v2.8M127 134.4v2.8M132.1 139.7v2.5M154.9 139.7h.1"/>
<path d="M154.9 139.7v1.3M162.6 139.7h.1M162.6 139.7v1.3M227.3 127h.1M227.3 127v1.3M227.3 133.4v3.8M227.3 139.7v2.5M43 154.9h8v2.6h-8l-1.1-1.3zM43 142.2h7.8v2.6h-7.8l-1.1-1.3zM43 146h7.8v2.6h-7.8l-1.1-1.3zM43 152.4h7.8v2.5h-7.8l-1.1-1.2zM43 148.6h8v2.5h-8l-1.1-1.2z"/>
<path d="M109.1 157.5h7.6v2.5h-7.6l-1.2-1.2zM121.9 156.2h2.6M121.9 151.1h2.6M121.9 148.6h2.6M121.9 153.7h2.6M139.7 151.1h2.5M139.7 148.6h2.5M154.9 146.1v1.2M162.6 146.1v1.2M220.8 148.6h6.4v2.5h-6.4l-1.1-1.2zM220.8 151.1h10v2.6h-10l-1.1-1.3zM220.8 153.7h6.7v2.5h-6.7l-1.1-1.3z"/>
<path d="M220.8 146h6.4v2.6h-6.4l-1.1-1.3zM39.2 176.5h9v2.6h-9l-1.1-1.3zM39.2 174h11.4v2.5h-11.4l-1.1-1.2zM100.2 165.1h8.3v2.5h-8.3l-1.1-1.2zM100.6 165.4h7M132.1 163.8h.1M132.1 161.3v2.5M138.5 170.2h7.7l1.1 1.3-1.1 1.2h-7.7zM161.3 166.4h.1M161.3 166.4v1.2M161.3 172.7v1.3M161.3 176.5v2.6"/>
<path d="M161.3 184.2h.1M161.3 181.6v2.6"/>
</g>
<path d="M202.4 51.3h4.1M202.4 52.8h4.1M202.4 74.2h4.1M202.4 75.7h4.1M161.8 97h4.1M161.8 98.6h4.1M202.4 97h4.1M202.4 98.6h4.1" fill="none" stroke="#840000" stroke-width=".51"/>
<path d="M121.8 62.2h12.2v2.6h-12.2l-1.2-1.3zM39.2 179.1h12.3v2.5h-12.3l-1.1-1.3z" fill="none" stroke="#840000" stroke-width=".16"/>
<path d="M150.6 146.3h2.6M150.6 148.8h4.9" fill="none" stroke="#0f0f0f" stroke-width=".15"/>
<path d="M106.7 162.6h8.9M115.6 162.6v12.7M115.6 175.3h33" fill="none" stroke="#008400" stroke-width=".15" stroke-dasharray="1.7 .6"/>
<g fill="none" stroke="#009600" stroke-width=".15">
<path d="M31.7 48.3h5.1M31.7 47v3.8M35.6 48.3v2.5h1.2M52.1 48.3h3.8M55.9 47v3.8M94 41.9v14M94 43.2h-5.1v1.3M193 45.7v1.3h11.5M204.5 45.7v2.6M231.1 45.7v6.4h28M231.1 57.2v5h28M242.6 57.2v2.5h16.5"/>
<path d="M242.6 45.7v3.8h16.5M254 45.7v1.3h5.1M254 57.2h5.1M80 62.2v1.3h3.8M104.1 63.5h8.9M193 68.6v1.3h11.5v1.2M257.8 69.9h1.3M257.8 72.4h1.3M259.1 67.3h-1.3v7.6M29.2 85.1h7.6M29.2 82.6v5M35.6 82.6v5h1.2"/>
<path d="M52.1 85.1h3.8M55.9 82.6v5M86.4 91.4v5.1M86.4 94h10.1M94 91.4v5.1h2.5M115.6 94v2.5M119.4 92.7v1.3M127 92.7v1.3M134.6 92.7v1.3M142.2 92.7v1.3h-30.4M193 91.4v1.3h22.9v1.3M204.5 92.7v1.3"/>
<path d="M132.1 127v12.7M132.1 128.3h-5.1v1.2M96.5 148.6h25.4M96.5 151.1h25.4M96.5 156.2h25.4M96.5 153.7h25.4M102.9 144.8v11.4M105.4 144.8v8.9M107.9 158.8h-1.2v3.8h-10.2M107.9 144.8v6.3M110.5 144.8v3.8M154.9 147.3v1.3h-12.7"/>
<path d="M162.6 147.3v3.8h-20.4M227.3 142.2v2.6h-7.6M30.5 174v6.3h7.6M34.3 174v3.8h3.8M36.8 174v1.3h1.3M96.5 166.4h2.6M147.3 171.5h1.3v3.8h12.7M161.3 174v2.5"/>
</g>
<path d="M21.8 32.4h44v33.6h-44zM75.6 35.6h59.7v39.3h-59.7zM140.2 36.1h38.1v38.8h-38.1zM185.4 32h93.5v80.3h-93.5zM17.8 69.2h48v49.9h-48zM75.6 78.1h73v33.7h-73zM152.4 78.7h25.4v33.1h-25.4zM69.3 115.1h104.4v79.2h-104.4zM198.9 116.8h62.7v42.6h-62.7zM20.3 129.5h40.7v57.2h-40.7z" fill="none" stroke="#0000c2" stroke-width=".15" stroke-dasharray="1.7 .6"/>
<path d="M91.5 175.9h7" fill="none" stroke="#0000c2" stroke-width=".15"/>
<path d="M85.8 172h7.3" fill="none" stroke="#f00" stroke-width=".25"/>
<path d="M125.1 155.1h2.4M134.2 150h4.9M136.4 147.5h2.7" fill="none" stroke="#006464" stroke-width=".15"/>
<g fill="#009600" stroke="#009600" stroke-width=".13">
<circle cx="55.9" cy="85.1" r=".46"/>
<circle cx="86.4" cy="94" r=".46"/>
<circle cx="29.2" cy="85.1" r=".46"/>
<circle cx="161.3" cy="175.3" r=".46"/>
<circle cx="132.1" cy="128.3" r=".46"/>
<circle cx="102.9" cy="156.2" r=".46"/>
<circle cx="105.4" cy="153.7" r=".46"/>
<circle cx="107.9" cy="151.1" r=".46"/>
<circle cx="110.5" cy="148.6" r=".46"/>
<circle cx="35.6" cy="48.3" r=".46"/>
<circle cx="55.9" cy="48.3" r=".46"/>
<circle cx="31.7" cy="48.3" r=".46"/>
<circle cx="94" cy="43.2" r=".46"/>
<circle cx="204.5" cy="92.7" r=".46"/>
<circle cx="204.5" cy="47" r=".46"/>
<circle cx="134.6" cy="94" r=".46"/>
<circle cx="127" cy="94" r=".46"/>
<circle cx="115.6" cy="94" r=".46"/>
<circle cx="119.4" cy="94" r=".46"/>
<circle cx="257.8" cy="69.9" r=".46"/>
<circle cx="257.8" cy="72.4" r=".46"/>
</g>
<use href="#words"/>
</svg>
